###############################################################
#  Generated by:      Cadence Innovus 20.13-s083_1
#  OS:                Linux x86_64(Host ID rice-503-20-north)
#  Generated on:      Thu May 26 02:44:10 2022
#  Design:            bgr_top
#  Command:           write_lef_abstract -5.8 -extractBlockObs /home/users/xingyuni/ee372/aloe-sky130/aloe/layout/output/lef/BGR_V1_4_33.lef
###############################################################

VERSION 5.8 ;

BUSBITCHARS "[]" ;
DIVIDERCHAR "/" ;

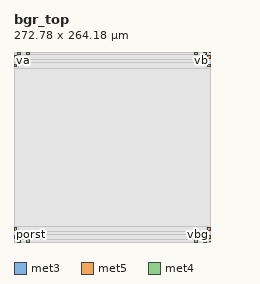
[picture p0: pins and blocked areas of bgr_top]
MACRO bgr_top
  CLASS BLOCK ;
  SIZE 272.780000 BY 264.180000 ;
  FOREIGN bgr_top 0.000000 0.000000 ;
  ORIGIN 0 0 ;
  SYMMETRY X Y R90 ;
  PIN porst
    DIRECTION INOUT ;
    USE SIGNAL ;
    PORT
      LAYER met3 ;
        RECT 0.000000 0.520000 0.800000 0.820000 ;
    END
  END porst
  PIN va
    DIRECTION INOUT ;
    USE SIGNAL ;
    PORT
      LAYER met3 ;
        RECT 0.000000 263.430000 0.800000 263.730000 ;
    END
  END va
  PIN vb
    DIRECTION INOUT ;
    USE SIGNAL ;
    PORT
      LAYER met3 ;
        RECT 271.980000 263.430000 272.780000 263.730000 ;
    END
  END vb
  PIN vbg
    DIRECTION INOUT ;
    USE SIGNAL ;
    PORT
      LAYER met3 ;
        RECT 271.980000 0.520000 272.780000 0.820000 ;
    END
  END vbg
  PIN VDD
    DIRECTION INOUT ;
    USE POWER ;
    PORT
      LAYER met5 ;
        RECT 0.000000 16.560000 4.000000 20.560000 ;
    END
    PORT
      LAYER met5 ;
        RECT 268.780000 16.560000 272.780000 20.560000 ;
    END
    PORT
      LAYER met5 ;
        RECT 0.000000 243.360000 4.000000 247.360000 ;
    END
    PORT
      LAYER met5 ;
        RECT 268.780000 243.360000 272.780000 247.360000 ;
    END
    PORT
      LAYER met4 ;
        RECT 16.980000 0.000000 20.980000 4.000000 ;
    END
    PORT
      LAYER met4 ;
        RECT 16.980000 260.180000 20.980000 264.180000 ;
    END
    PORT
      LAYER met4 ;
        RECT 251.600000 0.000000 255.600000 4.000000 ;
    END
    PORT
      LAYER met4 ;
        RECT 251.600000 260.180000 255.600000 264.180000 ;
    END
  END VDD
  PIN VSS
    DIRECTION INOUT ;
    USE GROUND ;
    PORT
      LAYER met5 ;
        RECT 0.000000 4.560000 4.000000 8.560000 ;
    END
    PORT
      LAYER met5 ;
        RECT 268.780000 4.560000 272.780000 8.560000 ;
    END
    PORT
      LAYER met5 ;
        RECT 0.000000 255.360000 4.000000 259.360000 ;
    END
    PORT
      LAYER met5 ;
        RECT 268.780000 255.360000 272.780000 259.360000 ;
    END
    PORT
      LAYER met4 ;
        RECT 4.980000 0.000000 8.980000 4.000000 ;
    END
    PORT
      LAYER met4 ;
        RECT 4.980000 260.180000 8.980000 264.180000 ;
    END
    PORT
      LAYER met4 ;
        RECT 263.600000 0.000000 267.600000 4.000000 ;
    END
    PORT
      LAYER met4 ;
        RECT 263.600000 260.180000 267.600000 264.180000 ;
    END
  END VSS
  OBS
    LAYER li1 ;
      RECT 0.000000 0.000000 272.780000 264.180000 ;
    LAYER met1 ;
      RECT 0.000000 0.000000 272.780000 264.180000 ;
    LAYER met2 ;
      RECT 0.000000 0.000000 272.780000 264.180000 ;
    LAYER met3 ;
      RECT 0.000000 264.130000 272.780000 264.180000 ;
      RECT 1.200000 263.030000 271.580000 264.130000 ;
      RECT 0.000000 1.220000 272.780000 263.030000 ;
      RECT 1.200000 0.120000 271.580000 1.220000 ;
      RECT 0.000000 0.000000 272.780000 0.120000 ;
    LAYER met4 ;
      RECT 268.000000 259.780000 272.780000 264.180000 ;
      RECT 256.000000 259.780000 263.200000 264.180000 ;
      RECT 21.380000 259.780000 251.200000 264.180000 ;
      RECT 9.380000 259.780000 16.580000 264.180000 ;
      RECT 0.000000 259.780000 4.580000 264.180000 ;
      RECT 0.000000 4.400000 272.780000 259.780000 ;
      RECT 268.000000 0.000000 272.780000 4.400000 ;
      RECT 256.000000 0.000000 263.200000 4.400000 ;
      RECT 21.380000 0.000000 251.200000 4.400000 ;
      RECT 9.380000 0.000000 16.580000 4.400000 ;
      RECT 0.000000 0.000000 4.580000 4.400000 ;
    LAYER met5 ;
      RECT 0.000000 260.960000 272.780000 264.180000 ;
      RECT 5.600000 253.760000 267.180000 260.960000 ;
      RECT 0.000000 248.960000 272.780000 253.760000 ;
      RECT 5.600000 241.760000 267.180000 248.960000 ;
      RECT 0.000000 22.160000 272.780000 241.760000 ;
      RECT 5.600000 14.960000 267.180000 22.160000 ;
      RECT 0.000000 10.160000 272.780000 14.960000 ;
      RECT 5.600000 2.960000 267.180000 10.160000 ;
      RECT 0.000000 0.000000 272.780000 2.960000 ;
  END
END bgr_top

END LIBRARY
